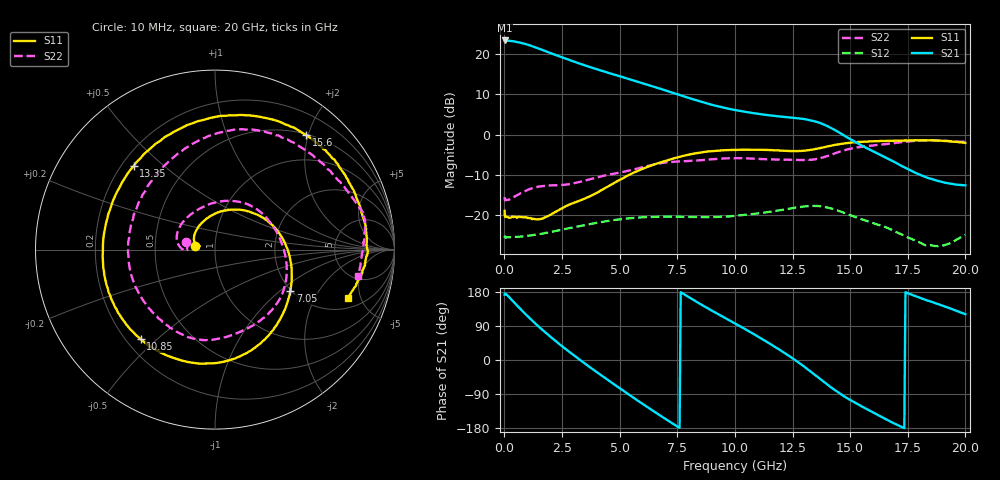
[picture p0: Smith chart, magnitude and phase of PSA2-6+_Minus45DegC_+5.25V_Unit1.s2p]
!Keysight Technologies,N5242A,MY47200155,A.10.49.08
!Date: Thursday, October 19, 2023 15:32:30
!Correction: S11(Full 2 Port(1,2))
!S21(Full 2 Port(1,2))
!S12(Full 2 Port(1,2))
!S22(Full 2 Port(1,2))
!S2P File: Measurements: S11, S21, S12, S22:
# Hz S  dB  R 50
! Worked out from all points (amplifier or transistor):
!   408 points, 10 MHz to 20 GHz, reference 50 ohm
!   highest |S21| = 23.2 dB at 10 MHz (marker M1)
!   |S21| within 3 dB of that: start of sweep to 1.944 GHz
!   unconditionally stable (mu >= 1): start of sweep to end of sweep
!   at 3.05 GHz: K = 1.08, MAG = 18.6 dB, |S12| = -22.9 dB
!   at 9.85 GHz: K = 1.11, MAG = 11.1 dB, |S12| = -20.2 dB
!   at 20 GHz: K = 4.31, MAG = -3.2 dB, |S12| = -24.8 dB
!   S11 on the Smith chart (normalised r, x): 10 MHz: 0.80, +0.03; 7.05 GHz: 1.98, -1.18; 10.85 GHz: 0.26, -0.44; 13.35 GHz: 0.25, +0.40; 15.6 GHz: 0.51, +1.96; 20 GHz: 2.74, -3.87
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1e7  -18.87 169.4  23.24 172.5  -25.54 -5.2  -15.47 165.5
7e7  -20.24 178.0  23.18 174.4  -25.43 -1.8  -16.20 179.0
3.5e8  -20.25 175.5  23.07 156.6  -25.35 -5.0  -15.60 -178.9
7e8  -20.37 171.3  22.68 134.4  -25.22 -9.8  -14.52 178.0
9.5e8  -20.44 168.6  22.30 119.1  -25.07 -13.3  -13.85 173.3
1.25e9  -20.80 166.0  21.73 101.5  -24.85 -17.9  -13.18 165.9
1.75e9  -20.51 169.5  20.66 74.1  -24.35 -26.1  -12.69 151.2
2.25e9  -19.07 165.8  19.59 48.7  -23.82 -35.4  -12.54 133.5
2.75e9  -17.53 151.4  18.56 24.6  -23.21 -45.5  -12.32 113.3
3.35e9  -16.15 126.8  17.35 -3.0  -22.54 -59.1  -11.59 89.4
4.1e9  -14.14 92.0  15.96 -36.0  -21.74 -77.6  -10.49 62.8
4.85e9  -11.67 58.4  14.66 -68.0  -21.07 -97.5  -9.57 36.1
5.85e9  -8.83 17.1  12.94 -109.9  -20.50 -125.2  -8.29 -0.6
6.7e9  -7.02 -16.3  11.42 -144.2  -20.31 -148.7  -7.17 -26.9
7.05e9  -6.39 -28.8  10.78 -158.0  -20.30 -158.3  -6.89 -36.6
8.45e9  -4.48 -70.3  8.24 149.4  -20.40 165.2  -6.39 -73.7
1.005e10  -3.80 -109.0  6.00 94.8  -20.06 128.0  -5.85 -103.0
1.085e10  -3.76 -129.7  5.23 67.2  -19.60 108.0  -5.97 -118.0
1.335e10  -3.74 134.2  3.43 -33.5  -17.67 30.2  -6.25 159.4
1.56e10  -1.76 51.5  -3.02 -125.6  -21.11 -47.0  -2.93 67.6
1.67e10  -1.57 28.8  -6.12 -160.9  -23.30 -76.4  -2.28 36.9
2e10  -2.06 -19.8  -12.57 120.8  -24.83 -112.3  -1.82 -10.6
